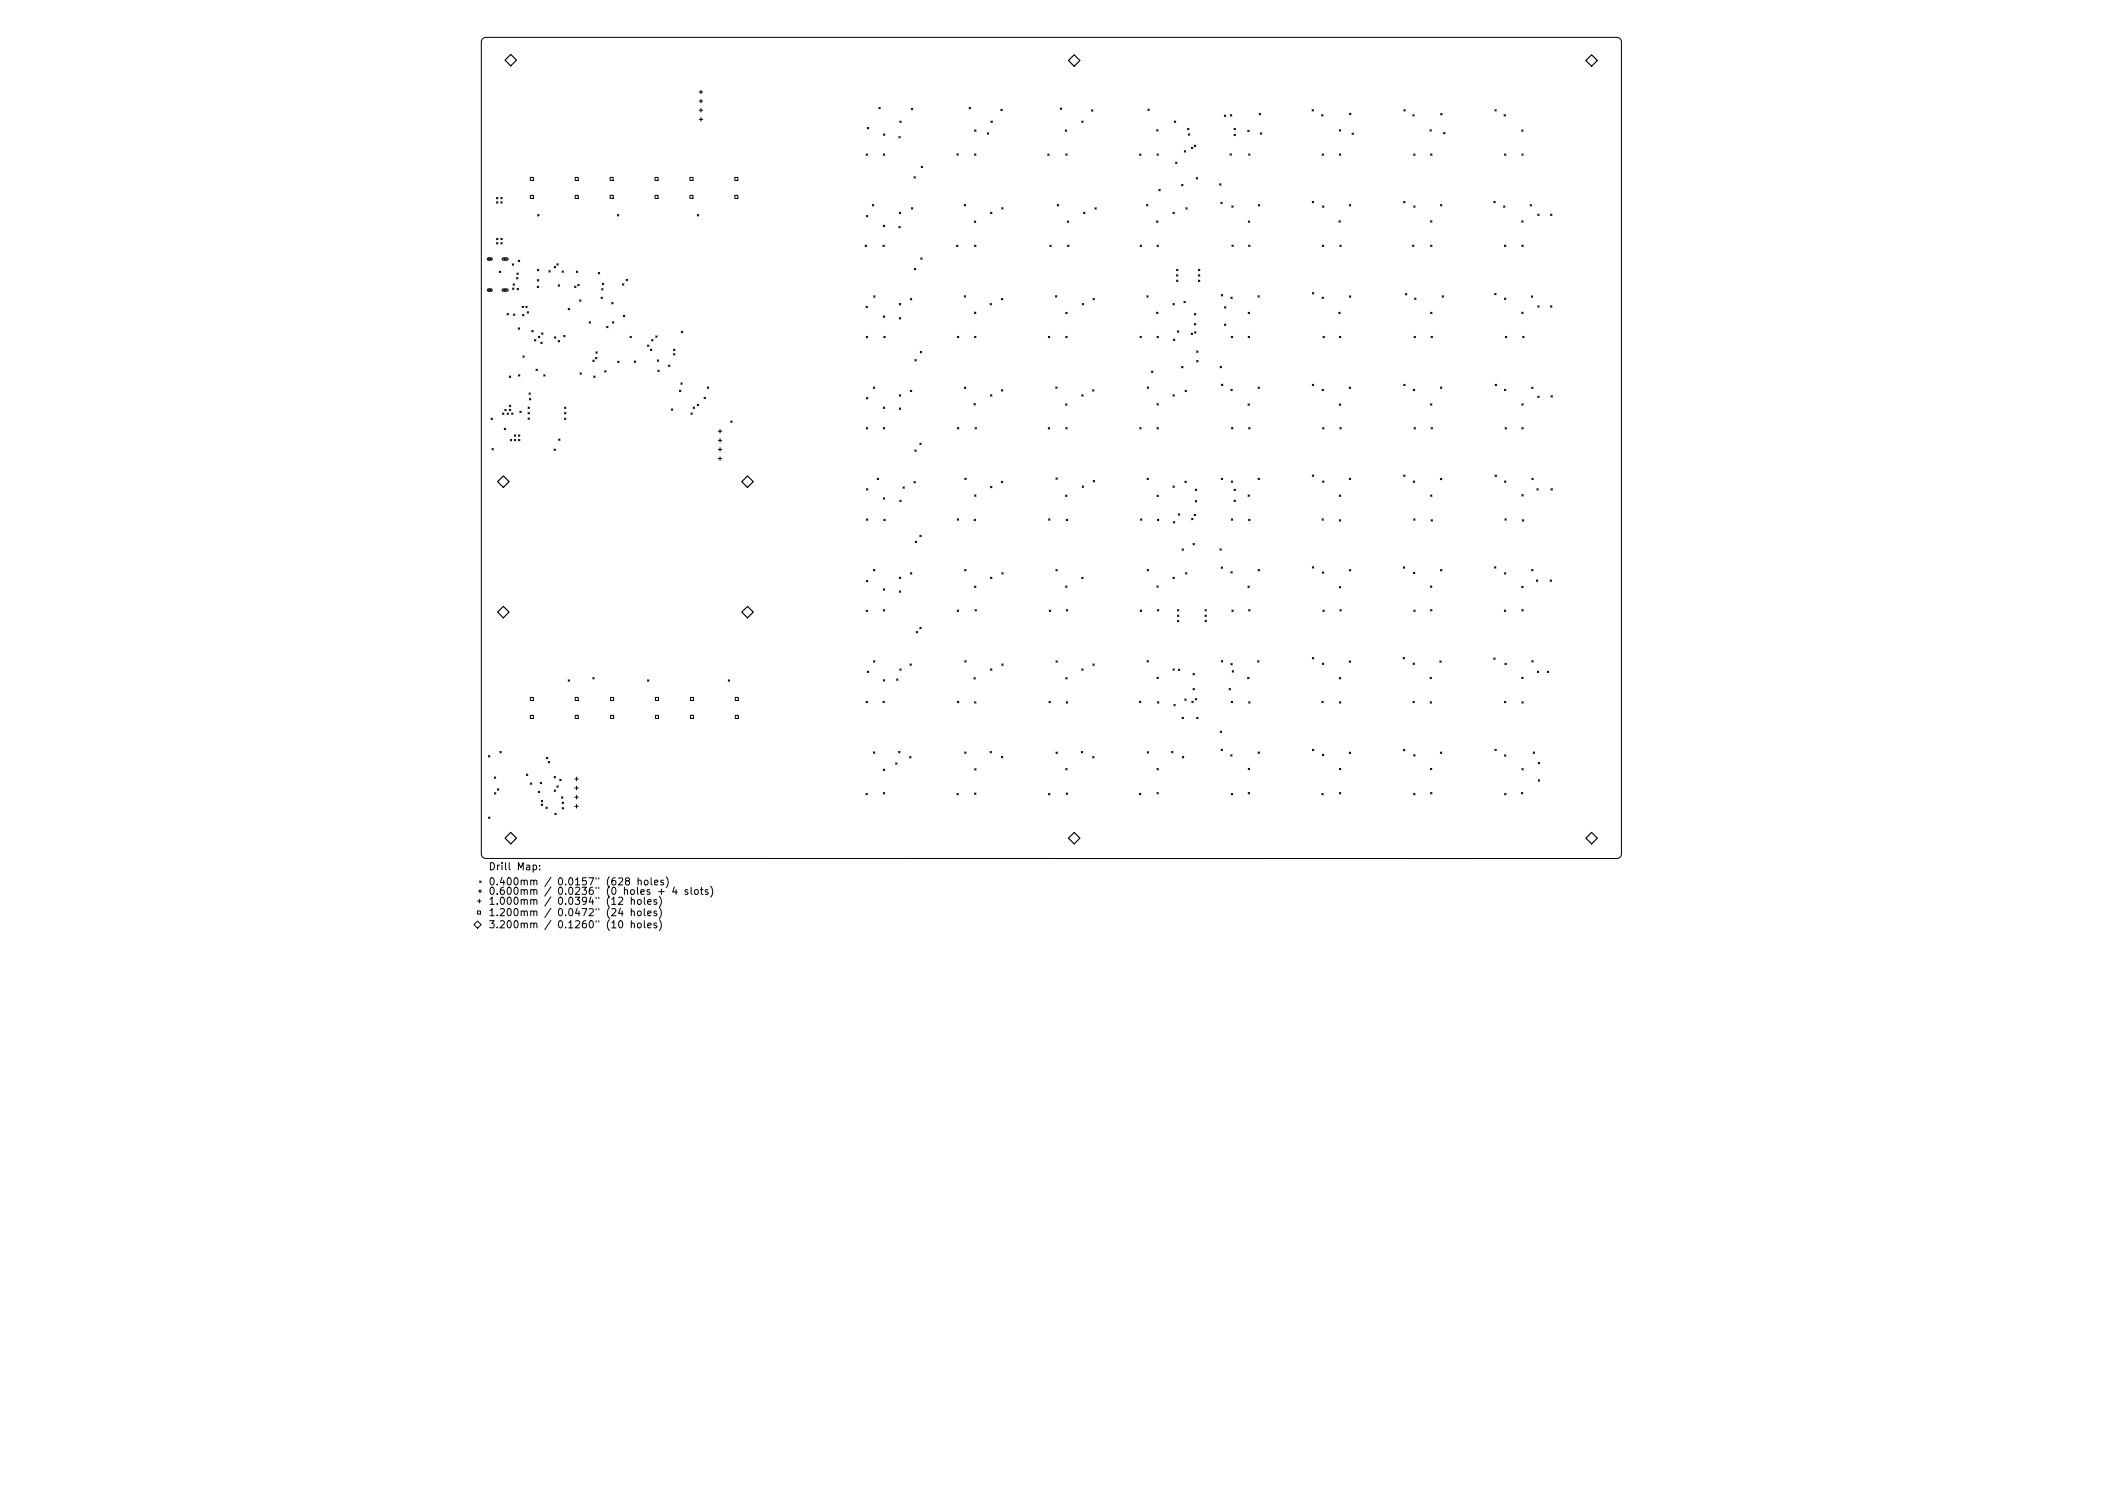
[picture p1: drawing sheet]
<svg xmlns="http://www.w3.org/2000/svg" width="297mm" height="210mm" viewBox="0 0 297 210" stroke-linecap="round" stroke-linejoin="round" font-family="sans-serif">
<defs><g id="words">
<g font-size="1.4">
<text x="69" y="122.9">Drill Map:</text>
<text x="69" y="125">0.400mm / 0.0157&quot; (628 holes)</text>
<text x="69" y="126.3">0.600mm / 0.0236&quot; (0 holes + 4 slots)</text>
<text x="69" y="127.8">1.000mm / 0.0394&quot; (12 holes)</text>
<text x="69" y="129.4">1.200mm / 0.0472&quot; (24 holes)</text>
<text x="69" y="131.1">3.200mm / 0.1260&quot; (10 holes)</text>
</g>
</g></defs>
<g fill="none" stroke="#000" stroke-width=".14">
<path d="M68.2 5.5l.4-.2h159.8a.64 .64 0 0 1 .6 .6v114.7a.65 .65 0 0 1-.6 .6h-159.8a.64 .64 0 0 1-.6-.6v-114.7zM98.8 13h.5M98.8 14.3h.5M98.8 15.6h.5M98.8 16.9h.5M99 12.7v.5M99 14v.5M99 15.3v.5M99 16.6v.5M122.5 18l.2 .2M122.7 18l-.2 .2M124.1 15.2l.2 .2"/>
<path d="M124.3 15.2l-.2 .2M124.8 18.9l.2 .2M125 18.9l-.2 .2M127 19.3l.2 .2M127.1 17.1l.2 .2M127.2 19.3l-.2 .2M127.3 17.1l-.2 .2M128.7 15.3l.2 .2M128.9 15.3l-.2 .2M136.9 15.2l.2 .2M137.1 15.2l-.2 .2M137.7 18.3l.2 .2"/>
<path d="M137.9 18.3l-.2 .2M139.5 18.8l.2 .2M139.7 18.8l-.2 .2M140 17.1l.2 .2M140.2 17.1l-.2 .2M141.4 15.4l.2 .2M141.6 15.4l-.2 .2M149.8 15.2l.2 .2M150 15.2l-.2 .2M150.5 18.3l.2 .2M150.7 18.3l-.2 .2M152.8 17.1l.2 .2"/>
<path d="M153 17.1l-.2 .2M154.2 15.5l.2 .2M154.4 15.5l-.2 .2M162.1 15.4l.2 .2M162.3 15.4l-.2 .2M163.4 18.3l.2 .2M163.6 18.3l-.2 .2M165.9 17.1l.2 .2M166.1 17.1l-.2 .2M167.7 18.1l.2 .2M167.9 18.9l.2 .2M167.9 18.1l-.2 .2"/>
<path d="M168.1 18.9l-.2 .2M172.9 16.3l.2 .2M173.1 16.3l-.2 .2M173.8 16.2l.2 .2M174 16.2l-.2 .2M174.3 18.1l.2 .2M174.3 19l.2 .2M174.5 18.1l-.2 .2M174.5 19l-.2 .2M176.2 18.4l.2 .2M176.4 18.4l-.2 .2M177.8 16l.3 .2"/>
<path d="M178 18.8l.2 .2M178.1 16l-.3 .2M178.2 18.8l-.2 .2M185.3 15.5l.2 .2M185.5 15.5l-.2 .2M186.7 16.2l.2 .2M186.9 16.2l-.2 .2M189.2 18.3l.2 .2M189.4 18.3l-.2 .2M190.6 16l.2 .2M190.8 16l-.2 .2M191 18.8l.2 .2"/>
<path d="M191.2 18.8l-.2 .2M198.3 15.5l.2 .2M198.5 15.5l-.2 .2M199.6 16.2l.2 .2M199.8 16.2l-.2 .2M202 18.3l.2 .2M202.2 18.3l-.2 .2M203.5 16l.2 .2M203.7 16l-.2 .2M203.9 18.7l.2 .2M204.1 18.7l-.2 .2M211.1 15.5l.2 .2"/>
<path d="M211.3 15.5l-.2 .2M212.4 16.2l.2 .2M212.6 16.2l-.2 .2M214.9 18.3l.2 .2M215.1 18.3l-.2 .2M68.9 36.5l.5-.1 .1 .2-.1 .1h-.5l-.1-.1zM70.1 27.9l.2 .2M70.1 28.5l.2 .2M70.1 33.6l.2 .2M70.1 34.3l.2 .2M70.3 27.9l-.2 .2M70.3 28.5l-.2 .2"/>
<path d="M70.3 33.6l-.2 .2M70.3 34.3l-.2 .2M70.5 38.3l.2 .2M70.7 38.3l-.2 .2M70.7 28.5l.2 .2M70.7 27.9l.2 .2M70.7 34.3l.2 .2M70.7 33.6l.2 .2M70.9 27.9l-.2 .2M70.9 28.5l-.2 .2M70.9 33.6l-.2 .2M70.9 34.3l-.2 .2"/>
<path d="M71 36.5l.6-.1 .2 .2-.2 .1h-.6l-.1-.1zM72.4 37.3l.2 .2M72.6 37.3l-.2 .2M73 39.2l.2 .2M73 38.6l.2 .2M73.2 39.2l-.2 .2M73.2 36.7l.2 .3M73.2 38.6l-.2 .2M73.4 36.7l-.2 .3M74.9 25h.4v.5h-.4zM74.9 27.6h.4v.4h-.4zM75.9 38l.2 .2"/>
<path d="M75.9 39.5l.2 .2M75.9 30.3l.2 .2M76.1 38l-.2 .2M76.1 39.5l-.2 .2M76.1 30.3l-.2 .2M77.5 38.2l.2 .2M77.7 38.2l-.2 .2M78.3 37.6l.2 .2M78.5 37.6l-.2 .2M78.7 37.2l.2 .2M78.9 37.2l-.2 .2M79.4 38.3l.2 .2"/>
<path d="M79.6 38.3l-.2 .2M81.2 25h.5v.5h-.5zM81.2 27.6h.5v.4h-.5zM81.4 38.3l.2 .2M81.6 38.3l-.2 .2M84.5 38.5l.2 .2M84.7 38.5l-.2 .2M85.1 40l.2 .2M85.3 40l-.2 .2M86.2 25h.4v.5h-.4zM86.2 27.6h.4v.4h-.4zM87.2 30.3l.2 .2"/>
<path d="M87.4 30.3l-.2 .2M88.4 39.4l.2 .2M88.6 39.4l-.2 .2M92.5 25h.4v.5h-.4zM92.5 27.6h.4v.4h-.4zM97.4 25h.5v.5h-.5zM97.4 27.6h.5v.4h-.5zM98.5 30.3l.2 .2M98.7 30.3l-.2 .2M103.8 25h.4v.5h-.4zM103.8 27.6h.4v.4h-.4zM122.2 34.6l.2 .2"/>
<path d="M122.3 21.7l.2 .2M122.4 30.4l.2 .2M122.4 34.6l-.2 .2M122.5 21.7l-.2 .2M122.6 30.4l-.2 .2M123.2 28.9l.2 .2M123.4 28.9l-.2 .2M124.7 34.6l.2 .2M124.8 31.8l.2 .2M124.8 21.7l.2 .2M124.9 34.6l-.2 .2M125 31.8l-.2 .2"/>
<path d="M125 21.7l-.2 .2M127 32l.2 .2M127 30l.2 .2M127.2 32l-.2 .2M127.2 30l-.2 .2M128.7 29.3l.2 .2M128.9 29.3l-.2 .2M129.1 24.9l.2 .3M129.1 37.9l.2 .2M129.3 24.9l-.2 .3M129.3 37.9l-.2 .2M130 36.4l.3 .2"/>
<path d="M130.1 23.5l.2 .2M130.3 36.4l-.3 .2M130.3 23.5l-.2 .2M135.1 34.6l.2 .2M135.2 21.7l.2 .2M135.3 34.6l-.2 .2M135.4 21.7l-.2 .2M136.2 28.9l.2 .2M136.4 28.9l-.2 .2M137.6 31.2l.2 .2M137.6 21.7l.3 .2M137.6 34.6l.3 .2"/>
<path d="M137.8 31.2l-.2 .2M137.9 21.7l-.3 .2M137.9 34.6l-.3 .2M139.9 30l.2 .2M140.1 30l-.2 .2M141.5 29.3l.2 .2M141.7 29.3l-.2 .2M148 21.7l.2 .2M148.2 21.7l-.2 .2M148.3 34.6l.2 .2M148.5 34.6l-.2 .2M149.3 28.9l.2 .2"/>
<path d="M149.5 28.9l-.2 .2M150.5 21.7l.2 .2M150.7 21.7l-.2 .2M150.8 31.2l.2 .2M150.8 34.6l.2 .2M151 31.2l-.2 .2M151 34.6l-.2 .2M153 30l.2 .2M153.2 30l-.2 .2M154.6 29.3l.2 .2M154.8 29.3l-.2 .2M160.9 21.7l.3 .2"/>
<path d="M161 34.6l.2 .2M161.2 21.7l-.3 .2M161.2 34.6l-.2 .2M161.9 28.9l.2 .2M162.1 28.9l-.2 .2M163.4 31.2l.2 .2M163.4 21.7l.2 .2M163.4 34.6l.2 .2M163.6 31.2l-.2 .2M163.6 21.7l-.2 .2M163.6 34.6l-.2 .2M163.7 26.8l.2 .2"/>
<path d="M163.9 26.8l-.2 .2M165.7 30l.2 .2M165.9 30l-.2 .2M166 22.9l.3 .2M166.2 38l.2 .2M166.2 38.8l.2 .2M166.2 39.5l.2 .2M166.3 22.9l-.3 .2M166.4 38l-.2 .2M166.4 38.8l-.2 .2M166.4 39.5l-.2 .2M166.9 26l.2 .2"/>
<path d="M167.1 26l-.2 .2M167.3 21.3l.2 .2M167.5 21.3l-.2 .2M167.5 29.3l.2 .2M167.7 29.3l-.2 .2M168.3 20.8l.2 .2M168.5 20.8l-.2 .2M168.7 20.5l.2 .2M168.9 20.5l-.2 .2M169 25.1l.2 .2M169.2 25.1l-.2 .2M169.3 38l.2 .2"/>
<path d="M169.3 38.8l.2 .2M169.3 39.6l.2 .2M169.5 38l-.2 .2M169.5 38.8l-.2 .2M169.5 39.6l-.2 .2M172.3 25.9l.2 .2M172.4 28.6l.2 .2M172.5 25.9l-.2 .2M172.6 28.6l-.2 .2M173.7 21.7l.2 .2M173.9 21.7l-.2 .2M174 29.1l.2 .2"/>
<path d="M174 34.6l.2 .2M174.2 29.1l-.2 .2M174.2 34.6l-.2 .2M176.3 31.2l.2 .2M176.4 21.7l.2 .2M176.4 34.6l.2 .2M176.5 31.2l-.2 .2M176.6 21.7l-.2 .2M176.6 34.6l-.2 .2M177.7 28.9l.2 .2M177.9 28.9l-.2 .2M185.3 28.4l.2 .2"/>
<path d="M185.5 28.4l-.2 .2M186.7 21.7l.2 .2M186.8 34.6l.2 .2M186.8 29.1l.2 .2M186.9 21.7l-.2 .2M187 34.6l-.2 .2M187 29.1l-.2 .2M189.1 31.2l.2 .2M189.2 21.7l.2 .2M189.2 34.6l.2 .2M189.3 31.2l-.2 .2M189.4 21.7l-.2 .2"/>
<path d="M189.4 34.6l-.2 .2M190.6 28.9l.2 .2M190.8 28.9l-.2 .2M198.3 28.4l.2 .2M198.5 28.4l-.2 .2M199.5 34.6l.2 .2M199.7 21.7l.2 .2M199.7 29.1l.2 .2M199.7 34.6l-.2 .2M199.9 21.7l-.2 .2M199.9 29.1l-.2 .2M202.1 31.2l.2 .2"/>
<path d="M202.1 34.6l.2 .2M202.1 21.7l.2 .2M202.3 31.2l-.2 .2M202.3 34.6l-.2 .2M202.3 21.7l-.2 .2M203.5 28.9l.2 .2M203.7 28.9l-.2 .2M211 28.4l.2 .2M211.2 28.4l-.2 .2M212.4 29.1l.2 .2M212.5 34.6l.2 .2M212.5 21.7l.2 .2"/>
<path d="M212.6 29.1l-.2 .2M212.7 34.6l-.2 .2M212.7 21.7l-.2 .2M214.9 31.2l.2 .2M214.9 21.7l.2 .2M214.9 34.6l.2 .2M215.1 31.2l-.2 .2M215.1 21.7l-.2 .2M215.1 34.6l-.2 .2M216.1 28.9l.2 .2M216.3 28.9l-.2 .2M217.2 30.2l.2 .2"/>
<path d="M217.4 30.2l-.2 .2M219 30.2l.2 .2M219.2 30.2l-.2 .2M68.9 40.9l.5-.1 .1 .2-.1 .1h-.5l-.1-.1zM69.4 59l.2 .2M69.6 59l-.2 .2M71 40.9l.6-.1 .2 .2-.2 .1h-.6l-.1-.1zM71 58.3l.2 .2M71.2 58.3l-.2 .2M71.3 57.8l.2 .2M71.5 57.8l-.2 .2M71.6 44.3l.2 .2"/>
<path d="M71.6 58.3l.2 .2M71.8 44.3l-.2 .2M71.8 58.3l-.2 .2M71.9 53.1l.2 .2M71.9 57.2l.2 .2M71.9 57.8l.2 .2M72.1 53.1l-.2 .2M72.1 57.2l-.2 .2M72.1 57.8l-.2 .2M72.3 58.3l.2 .2M72.4 40.7l.2 .2M72.5 58.3l-.2 .2"/>
<path d="M72.5 40.1l.2 .2M72.5 44.3l.2 .2M72.6 40.7l-.2 .2M72.7 40.1l-.2 .2M72.7 44.3l-.2 .2M73 40.7l.2 .2M73.2 46.3l.2 .2M73.2 52.9l.2 .2M73.2 40.7l-.2 .2M73.4 46.3l-.2 .2M73.4 58.1l.2 .2M73.4 52.9l-.2 .2"/>
<path d="M73.6 58.1l-.2 .2M73.7 43.2l.2 .2M73.8 44.4l.2 .2M73.9 50.2l.2 .3M73.9 43.2l-.2 .2M74 44.4l-.2 .2M74.1 50.2l-.2 .3M74.3 43.2l.2 .2M74.5 44l.2 .2M74.5 43.2l-.2 .2M74.6 57.5l.2 .2M74.6 58.2l.2 .3"/>
<path d="M74.6 59l.2 .2M74.7 44l-.2 .2M74.7 55.5l.2 .2M74.8 56.3l.2 .2M74.8 58.2l-.2 .3M74.8 57.5l-.2 .2M74.8 59l-.2 .2M74.9 55.5l-.2 .2M75 56.3l-.2 .2M75.1 46.7l.2 .2M75.3 46.7l-.2 .2M75.5 48l.2 .2"/>
<path d="M75.7 48l-.2 .2M75.7 52.1l.2 .2M75.9 40.4l.2 .2M75.9 52.1l-.2 .2M76 47.5l.2 .2M76.1 40.4l-.2 .2M76.2 47.5l-.2 .2M76.4 48.3l.2 .2M76.5 47l.2 .2M76.6 48.3l-.2 .2M76.7 47l-.2 .2M76.8 52.9l.2 .2"/>
<path d="M77 52.9l-.2 .2M78.3 47.6l.2 .2M78.5 47.6l-.2 .2M78.8 48.1l.2 .2M78.8 40.2l.2 .2M79 40.2l-.2 .2M79 48.1l-.2 .2M79.6 47.4l.2 .2M79.7 57.5l.2 .2M79.7 58.2l.2 .3M79.7 59l.2 .2M79.8 47.4l-.2 .2"/>
<path d="M79.9 57.5l-.2 .2M79.9 58.2l-.2 .3M79.9 59l-.2 .2M80.3 43.5l.2 .2M80.5 43.5l-.2 .2M81.2 40.4l.2 .2M81.4 40.4l-.2 .2M81.6 40.1l.2 .3M81.8 40.1l-.2 .3M81.9 42.3l.2 .2M81.9 52.6l.2 .2M82.1 42.3l-.2 .2"/>
<path d="M82.1 52.6l-.2 .2M83.2 45.4l.2 .2M83.4 45.4l-.2 .2M83.7 50.8l.2 .2M83.9 53.1l.2 .2M83.9 50.8l-.2 .2M84.1 53.1l-.2 .2M84.1 50.5l.2 .2M84.2 49.7l.2 .2M84.3 50.5l-.2 .2M84.4 49.7l-.2 .2M84.9 42l.2 .2"/>
<path d="M85 40.8l.2 .2M85.1 42l-.2 .2M85.2 40.8l-.2 .2M85.4 52.3l.2 .2M85.6 52.3l-.2 .2M85.7 46.1l.2 .2M85.9 46.1l-.2 .2M86.4 42.7l.2 .2M86.5 45.4l.2 .2M86.6 42.7l-.2 .2M86.7 45.4l-.2 .2M87.2 51l.2 .2"/>
<path d="M87.4 51l-.2 .2M87.9 40.1l.2 .2M88 44.5l.2 .2M88.1 40.1l-.2 .2M88.2 44.5l-.2 .2M89 47.5l.2 .2M89.2 47.5l-.2 .2M89.6 51l.2 .2M89.8 51l-.2 .2M91.5 48.7l.2 .2M91.7 48.7l-.2 .2M91.9 49.3l.2 .2"/>
<path d="M92 47.9l.2 .2M92.1 49.3l-.2 .2M92.2 47.9l-.2 .2M92.6 47.4l.2 .2M92.8 47.4l-.2 .2M92.8 50.8l.2 .2M92.9 52.3l.2 .2M93 50.8l-.2 .2M93.1 52.3l-.2 .2M94.4 51.6l.2 .2M94.6 51.6l-.2 .2M94.8 57.7l.2 .2"/>
<path d="M95 57.7l-.2 .2M95.1 49.9l.2 .2M95.1 49.3l.2 .2M95.3 49.3l-.2 .2M95.3 49.9l-.2 .2M96 55.1l.2 .2M96.2 54.1l.2 .2M96.2 55.1l-.2 .2M96.2 46.8l.2 .2M96.4 54.1l-.2 .2M96.4 46.8l-.2 .2M97.6 58.3l.2 .2"/>
<path d="M97.8 58.3l-.2 .2M97.9 57.5l.2 .2M98.1 57.5l-.2 .2M98.5 57.1l.2 .2M98.7 57.1l-.2 .2M99.4 56.1l.2 .2M99.6 56.1l-.2 .2M99.9 54.6l.2 .2M100.1 54.6l-.2 .2M103.2 59.4l.2 .2M103.4 59.4l-.2 .2M122.3 43.2l.2 .2"/>
<path d="M122.3 47.5l.2 .2M122.4 56.1l.2 .2M122.5 43.2l-.2 .2M122.5 47.5l-.2 .2M122.6 56.1l-.2 .2M123.3 54.6l.3 .3M123.4 41.8l.2 .2M123.6 54.6l-.3 .3M123.6 41.8l-.2 .2M124.8 57.5l.2 .2M124.8 44.6l.2 .2M124.8 47.5l.2 .2"/>
<path d="M125 57.5l-.2 .2M125 44.6l-.2 .2M125 47.5l-.2 .2M127 42.9l.2 .2M127 44.9l.2 .2M127 55.7l.2 .2M127 57.6l.2 .2M127.2 55.7l-.2 .2M127.2 42.9l-.2 .2M127.2 44.9l-.2 .2M127.2 57.6l-.2 .2M128.6 42.2l.2 .2"/>
<path d="M128.6 55.1l.2 .2M128.8 42.2l-.2 .2M128.8 55.1l-.2 .2M129.2 50.8l.2 .2M129.4 50.8l-.2 .2M130 49.6l.2 .2M130.2 49.6l-.2 .2M135.2 47.5l.2 .2M135.4 47.5l-.2 .2M136.2 41.8l.2 .2M136.2 54.7l.2 .2M136.4 41.8l-.2 .2"/>
<path d="M136.4 54.7l-.2 .2M137.6 57l.2 .2M137.6 44.1l.2 .2M137.6 47.5l.3 .2M137.8 57l-.2 .2M137.8 44.1l-.2 .2M137.9 47.5l-.3 .2M139.8 42.9l.2 .2M139.9 55.7l.2 .2M140 42.9l-.2 .2M140.1 55.7l-.2 .2M141.4 42.1l.2 .2"/>
<path d="M141.4 55l.2 .2M141.6 42.1l-.2 .2M141.6 55l-.2 .2M148.1 47.5l.2 .2M148.3 47.5l-.2 .2M149.1 41.8l.2 .2M149.1 54.6l.2 .2M149.3 41.8l-.2 .2M149.3 54.6l-.2 .2M150.5 57l.2 .2M150.5 47.5l.2 .2M150.5 44.1l.2 .2"/>
<path d="M150.7 57l-.2 .2M150.7 47.5l-.2 .2M150.7 44.1l-.2 .2M152.8 55.7l.2 .2M152.9 42.9l.2 .2M153 55.7l-.2 .2M153.1 42.9l-.2 .2M154.3 55l.2 .2M154.4 42.1l.2 .2M154.5 55l-.2 .2M154.6 42.1l-.2 .2M161 47.5l.2 .2"/>
<path d="M161.2 47.5l-.2 .2M162 41.8l.2 .2M162 54.6l.2 .2M162.2 41.8l-.2 .2M162.2 54.6l-.2 .2M162.6 52.4l.2 .2M162.8 52.4l-.2 .2M163.4 44.1l.2 .2M163.4 57l.2 .2M163.4 47.5l.2 .2M163.6 44.1l-.2 .2M163.6 57l-.2 .2"/>
<path d="M163.6 47.5l-.2 .2M165.7 42.9l.2 .2M165.7 55.7l.2 .2M165.7 47.9l.2 .2M165.9 42.9l-.2 .2M165.9 55.7l-.2 .2M165.9 47.9l-.2 .2M166.3 46.7l.2 .2M166.5 46.7l-.2 .2M166.9 51.7l.2 .2M167.1 51.7l-.2 .2M167.2 42.5l.2 .3"/>
<path d="M167.4 55.1l.2 .2M167.4 42.5l-.2 .3M167.6 55.1l-.2 .2M168.2 47l.2 .2M168.4 47l-.2 .2M168.7 45.7l.2 .2M168.7 44.3l.2 .2M168.7 46.8l.2 .2M168.9 44.3l-.2 .2M168.9 45.7l-.2 .2M168.9 46.8l-.2 .2M169 49.6l.2 .2"/>
<path d="M169 50.9l.2 .2M169.2 49.6l-.2 .2M169.2 50.9l-.2 .2M172.3 51.7l.2 .2M172.5 41.6l.2 .2M172.5 54.2l.2 .3M172.5 51.7l-.2 .2M172.7 41.6l-.2 .2M172.7 54.2l-.2 .3M172.9 43.3l.3 .2M172.9 45.8l.3 .2M173.2 43.3l-.3 .2"/>
<path d="M173.2 45.8l-.3 .2M173.8 42l.3 .2M173.8 55l.3 .2M173.9 47.5l.2 .2M174.1 42l-.3 .2M174.1 55l-.3 .2M174.1 47.5l-.2 .2M176.3 57l.2 .2M176.3 44.1l.2 .2M176.3 47.5l.2 .2M176.5 57l-.2 .2M176.5 44.1l-.2 .2"/>
<path d="M176.5 47.5l-.2 .2M177.7 41.8l.2 .2M177.7 54.6l.2 .3M177.9 41.8l-.2 .2M177.9 54.6l-.2 .3M185.4 54.3l.2 .2M185.4 41.3l.2 .2M185.6 54.3l-.2 .2M185.6 41.3l-.2 .2M186.7 42l.2 .2M186.7 55l.2 .2M186.9 47.5l.2 .2"/>
<path d="M186.9 42l-.2 .2M186.9 55l-.2 .2M187.1 47.5l-.2 .2M189.1 44.1l.2 .2M189.2 57l.2 .2M189.2 47.5l.2 .2M189.3 44.1l-.2 .2M189.4 57l-.2 .2M189.4 47.5l-.2 .2M190.6 54.7l.2 .2M190.6 41.8l.2 .2M190.8 54.7l-.2 .2"/>
<path d="M190.8 41.8l-.2 .2M198.3 54.3l.2 .2M198.5 54.3l-.2 .2M198.5 41.4l.2 .2M198.7 41.4l-.2 .2M199.6 55l.2 .2M199.7 47.5l.2 .2M199.8 42.1l.2 .2M199.8 55l-.2 .2M199.9 47.5l-.2 .2M200 42.1l-.2 .2M202.1 57l.2 .2"/>
<path d="M202.1 44.1l.2 .2M202.1 47.5l.2 .2M202.3 57l-.2 .2M202.3 44.1l-.2 .2M202.3 47.5l-.2 .2M203.5 54.6l.2 .2M203.7 54.6l-.2 .2M203.7 41.8l.2 .2M203.9 41.8l-.2 .2M211.1 41.4l.2 .2M211.2 54.3l.2 .2M211.3 41.4l-.2 .2"/>
<path d="M211.4 54.3l-.2 .2M212.5 42.1l.2 .2M212.5 55l.2 .2M212.6 47.5l.2 .2M212.7 42.1l-.2 .2M212.7 55l-.2 .2M212.8 47.5l-.2 .2M214.9 44.1l.2 .2M214.9 57l.2 .2M215.1 47.5l.2 .2M215.1 44.1l-.2 .2M215.1 57l-.2 .2"/>
<path d="M215.3 47.5l-.2 .2M216.3 41.8l.2 .2M216.3 54.7l.2 .2M216.5 41.8l-.2 .2M216.5 54.7l-.2 .2M217.2 43.2l.2 .2M217.2 55.9l.2 .2M217.4 43.2l-.2 .2M217.4 55.9l-.2 .2M219 43.2l.2 .2M219.1 55.9l.2 .2M219.2 43.2l-.2 .2"/>
<path d="M219.3 55.9l-.2 .2M69.5 63.3l.2 .2M69.7 63.3l-.2 .2M71.2 60.5l.2 .2M71.4 60.5l-.2 .2M72.1 62l.2 .3M72.3 62l-.2 .3M72.6 61.4l.3 .2M72.6 62l.3 .3M72.9 61.4l-.3 .2M72.9 62l-.3 .3M73.2 61.4l.2 .2"/>
<path d="M73.2 62l.2 .3M73.4 61.4l-.2 .2M73.4 62l-.2 .3M78.3 63.4l.2 .2M78.5 63.4l-.2 .2M78.9 62l.2 .2M79.1 62l-.2 .2M101.4 60.9h.6M101.4 62.2h.6M101.4 63.5h.6M101.4 64.8h.6M101.7 60.6v.5"/>
<path d="M101.7 61.9v.5M101.7 63.2v.5M101.7 64.5v.5M122.4 60.4l.2 .2M122.4 73.3l.2 .2M122.4 69l.2 .2M122.6 60.4l-.2 .2M122.6 73.3l-.2 .2M122.6 69l-.2 .2M123.9 67.5l.2 .2M124.1 67.5l-.2 .2M124.8 70.3l.2 .2"/>
<path d="M124.8 60.4l.2 .2M124.8 73.3l.2 .2M125 70.3l-.2 .2M125 60.4l-.2 .2M125 73.3l-.2 .2M127.1 70.6l.2 .2M127.3 70.6l-.2 .2M127.5 68.7l.2 .3M127.7 68.7l-.2 .3M129.1 68l.2 .2M129.2 63.5l.2 .2M129.3 76.4l.2 .2"/>
<path d="M129.3 68l-.2 .2M129.4 63.5l-.2 .2M129.5 76.4l-.2 .2M129.9 62.6l.2 .2M129.9 75.6l.2 .2M130.1 62.6l-.2 .2M130.1 75.6l-.2 .2M135.2 73.3l.2 .2M135.2 60.4l.2 .2M135.4 73.3l-.2 .2M135.4 60.4l-.2 .2M136.3 67.5l.2 .2"/>
<path d="M136.5 67.5l-.2 .2M137.6 73.3l.2 .2M137.7 69.9l.2 .2M137.7 60.4l.2 .2M137.8 73.3l-.2 .2M137.9 69.9l-.2 .2M137.9 60.4l-.2 .2M139.9 68.7l.2 .2M140.1 68.7l-.2 .2M141.4 68l.2 .2M141.6 68l-.2 .2M148.1 60.4l.2 .2"/>
<path d="M148.1 73.3l.2 .2M148.3 60.4l-.2 .2M148.3 73.3l-.2 .2M149.1 67.5l.2 .2M149.3 67.5l-.2 .2M150.5 69.9l.2 .2M150.5 60.4l.2 .2M150.6 73.3l.2 .2M150.7 69.9l-.2 .2M150.7 60.4l-.2 .2M150.8 73.3l-.2 .2M152.9 68.6l.2 .2"/>
<path d="M153.1 68.6l-.2 .2M154.4 67.9l.2 .2M154.6 67.9l-.2 .2M161 60.4l.2 .2M161.1 73.3l.2 .2M161.2 60.4l-.2 .2M161.3 73.3l-.2 .2M162 67.5l.2 .2M162.2 67.5l-.2 .2M163.4 60.4l.2 .2M163.4 69.9l.2 .2M163.5 73.3l.2 .2"/>
<path d="M163.6 60.4l-.2 .2M163.6 69.9l-.2 .2M163.7 73.3l-.2 .2M165.7 68.6l.2 .2M165.7 73.7l.2 .2M165.9 68.6l-.2 .2M165.9 73.7l-.2 .2M166.4 72.5l.2 .3M166.6 72.5l-.2 .3M167 77.5l.2 .2M167.2 77.5l-.2 .2M167.4 67.9l.2 .2"/>
<path d="M167.6 67.9l-.2 .2M168.3 73.2l.2 .2M168.5 76.7l.2 .2M168.5 73.2l-.2 .2M168.7 72.6l.2 .2M168.7 76.7l-.2 .2M168.8 69.1l.2 .2M168.8 70.7l.2 .2M168.9 72.6l-.2 .2M169 69.1l-.2 .2M169 70.7l-.2 .2M172.3 77.5l.2 .2"/>
<path d="M172.5 77.5l-.2 .2M172.5 67.5l.2 .2M172.7 67.5l-.2 .2M173.9 67.9l.2 .2M173.9 73.3l.2 .2M173.9 60.4l.2 .2M174.1 67.9l-.2 .2M174.1 73.3l-.2 .2M174.1 60.4l-.2 .2M174.3 69.1l.2 .2M174.3 70.6l.2 .2M174.5 69.1l-.2 .2"/>
<path d="M174.5 70.6l-.2 .2M176.3 69.9l.2 .2M176.4 60.4l.2 .2M176.4 73.3l.2 .2M176.5 69.9l-.2 .2M176.6 60.4l-.2 .2M176.6 73.3l-.2 .2M177.7 67.5l.2 .2M177.9 67.5l-.2 .2M185.4 67.1l.2 .2M185.6 67.1l-.2 .2M186.7 73.3l.2 .2"/>
<path d="M186.8 67.9l.2 .2M186.8 60.4l.2 .2M186.9 73.3l-.2 .2M187 67.9l-.2 .2M187 60.4l-.2 .2M189.2 69.9l.2 .2M189.2 73.4l.2 .2M189.2 60.4l.2 .2M189.4 69.9l-.2 .2M189.4 73.4l-.2 .2M189.4 60.4l-.2 .2M190.6 67.5l.2 .2"/>
<path d="M190.8 67.5l-.2 .2M198.3 67.1l.2 .2M198.5 67.1l-.2 .2M199.6 67.9l.2 .2M199.7 73.3l.2 .2M199.7 60.4l.2 .2M199.8 67.9l-.2 .2M199.9 73.3l-.2 .2M199.9 60.4l-.2 .2M202.1 69.9l.2 .2M202.1 60.4l.2 .2M202.1 73.4l.2 .2"/>
<path d="M202.3 69.9l-.2 .2M202.3 60.4l-.2 .2M202.3 73.4l-.2 .2M203.4 67.5l.2 .2M203.6 67.5l-.2 .2M211.2 67.1l.2 .2M211.4 67.1l-.2 .2M212.5 67.9l.2 .2M212.6 73.3l.2 .2M212.6 60.4l.2 .2M212.7 67.9l-.2 .2M212.8 73.3l-.2 .2"/>
<path d="M212.8 60.4l-.2 .2M214.9 69.8l.2 .2M214.9 60.4l.2 .2M215 73.4l.2 .2M215.1 69.8l-.2 .2M215.1 60.4l-.2 .2M215.2 73.4l-.2 .2M216.4 67.5l.2 .2M216.6 67.5l-.2 .2M217.1 69l.2 .2M217.3 69l-.2 .2M219.1 69l.2 .2"/>
<path d="M219.3 69l-.2 .2M74.9 98.5h.4v.4h-.4zM80.3 96l.2 .2M80.5 96l-.2 .2M81.2 98.5h.5v.4h-.5zM83.7 95.7l.2 .2M83.9 95.7l-.2 .2M86.2 98.5h.5v.4h-.5zM91.5 96l.2 .2M91.7 96l-.2 .2M92.6 98.5h.4v.4h-.4zM97.5 98.5h.4v.4h-.4z"/>
<path d="M102.9 96l.2 .2M103.1 96l-.2 .2M103.9 98.5h.4v.4h-.4zM122.3 86.2l.2 .2M122.3 99l.2 .2M122.4 82l.2 .2M122.5 94.8l.2 .2M122.5 86.2l-.2 .2M122.5 99l-.2 .2M122.6 82l-.2 .2M122.7 94.8l-.2 .2M123.4 80.4l.2 .2"/>
<path d="M123.4 93.3l.2 .2M123.6 80.4l-.2 .2M123.6 93.3l-.2 .2M124.7 99l.2 .2M124.8 83.1l.2 .3M124.8 86.1l.2 .2M124.8 96l.2 .2M124.9 99l-.2 .2M125 83.1l-.2 .3M125 86.1l-.2 .2M125 96l-.2 .2M126.6 95.9l.2 .2"/>
<path d="M126.8 95.9l-.2 .2M127 81.5l.2 .2M127 83.4l.2 .2M127.1 94.4l.2 .3M127.2 81.5l-.2 .2M127.2 83.4l-.2 .2M127.3 94.4l-.2 .3M128.5 93.7l.2 .3M128.6 80.9l.2 .2M128.7 93.7l-.2 .3M128.8 80.9l-.2 .2M129.4 89.2l.2 .2"/>
<path d="M129.6 89.2l-.2 .2M129.9 88.6l.2 .2M130.1 88.6l-.2 .2M135.2 86.1l.2 .2M135.2 99l.2 .2M135.4 86.1l-.2 .2M135.4 99l-.2 .2M136.3 80.4l.2 .2M136.3 93.3l.2 .2M136.5 80.4l-.2 .2M136.5 93.3l-.2 .2M137.6 95.7l.2 .2"/>
<path d="M137.6 82.8l.2 .2M137.6 99.1l.3 .2M137.7 86.1l.2 .2M137.8 95.7l-.2 .2M137.8 82.8l-.2 .2M137.9 99.1l-.3 .2M137.9 86.1l-.2 .2M139.9 81.5l.2 .2M139.9 94.4l.2 .3M140.1 94.4l-.2 .3M140.1 81.5l-.2 .2M141.5 93.7l.2 .3"/>
<path d="M141.5 80.9l.2 .2M141.7 93.7l-.2 .3M141.7 80.9l-.2 .2M148.2 99l.2 .2M148.2 86.1l.2 .2M148.4 99l-.2 .2M148.4 86.1l-.2 .2M149.1 80.4l.2 .2M149.1 93.3l.3 .2M149.3 80.4l-.2 .2M149.4 93.3l-.3 .2M150.5 82.7l.2 .2"/>
<path d="M150.5 95.7l.2 .2M150.6 86.1l.2 .2M150.6 99.1l.2 .2M150.7 82.7l-.2 .2M150.7 95.7l-.2 .2M150.8 86.1l-.2 .2M150.8 99.1l-.2 .2M152.8 81.5l.2 .2M152.8 94.4l.2 .3M153 81.5l-.2 .2M153 94.4l-.2 .3M154.4 93.8l.2 .2"/>
<path d="M154.6 93.8l-.2 .2M160.9 99l.2 .2M161 86.1l.3 .2M161.1 99l-.2 .2M161.3 86.1l-.3 .2M162 93.3l.2 .2M162 80.4l.2 .2M162.2 93.3l-.2 .2M162.2 80.4l-.2 .2M163.4 82.7l.2 .2M163.4 95.6l.2 .2M163.5 86.1l.2 .2"/>
<path d="M163.5 99.1l.2 .2M163.6 82.7l-.2 .2M163.6 95.6l-.2 .2M163.7 99.1l-.2 .2M163.7 86.1l-.2 .2M165.7 81.5l.2 .2M165.7 94.4l.2 .3M165.8 99.5l.2 .2M165.9 81.5l-.2 .2M165.9 94.4l-.2 .3M166 99.5l-.2 .2M166.3 86.1l.2 .2"/>
<path d="M166.3 86.8l.2 .3M166.3 87.6l.2 .2M166.4 94.5l.2 .2M166.5 86.1l-.2 .2M166.5 86.8l-.2 .3M166.5 87.6l-.2 .2M166.6 94.5l-.2 .2M167.3 98.7l.2 .2M167.4 80.9l.2 .2M167.5 98.7l-.2 .2M167.6 80.9l-.2 .2M168.3 99l.2 .2"/>
<path d="M168.5 97.2l.2 .2M168.5 95.1l.2 .2M168.5 99l-.2 .2M168.7 95.1l-.2 .2M168.7 97.2l-.2 .2M168.8 98.6l.2 .2M169 98.6l-.2 .2M170.2 86.1l.2 .2M170.2 86.8l.2 .3M170.2 87.6l.2 .2M170.4 86.1l-.2 .2M170.4 86.8l-.2 .3"/>
<path d="M170.4 87.6l-.2 .2M172.5 80.1l.2 .2M172.5 93.3l.2 .2M172.7 80.1l-.2 .2M172.7 93.3l-.2 .2M173.6 97.2l.2 .2M173.8 97.2l-.2 .2M173.8 80.7l.3 .2M173.8 93.7l.3 .2M173.9 99l.2 .2M174 86.1l.2 .2M174 94.7l.2 .2"/>
<path d="M174.1 80.7l-.3 .2M174.1 93.7l-.3 .2M174.1 99l-.2 .2M174.2 86.1l-.2 .2M174.2 94.7l-.2 .2M176.2 95.6l.2 .2M176.3 82.8l.2 .2M176.4 86.1l.2 .2M176.4 99.1l.2 .2M176.4 95.6l-.2 .2M176.5 82.8l-.2 .2M176.6 86.1l-.2 .2"/>
<path d="M176.6 99.1l-.2 .2M177.6 93.3l.2 .2M177.7 80.4l.2 .2M177.8 93.3l-.2 .2M177.9 80.4l-.2 .2M185.4 80l.2 .2M185.4 92.8l.2 .2M185.6 80l-.2 .2M185.6 92.8l-.2 .2M186.7 99l.2 .2M186.8 80.8l.2 .2M186.8 93.6l.2 .2"/>
<path d="M186.9 86.1l.2 .2M186.9 99l-.2 .2M187 80.8l-.2 .2M187 93.6l-.2 .2M187.1 86.1l-.2 .2M189.2 95.7l.2 .2M189.2 82.8l.2 .2M189.2 99.1l.2 .2M189.2 86.1l.2 .2M189.4 95.7l-.2 .2M189.4 82.8l-.2 .2M189.4 99.1l-.2 .2"/>
<path d="M189.4 86.1l-.2 .2M190.6 93.3l.2 .2M190.6 80.4l.2 .2M190.8 93.3l-.2 .2M190.8 80.4l-.2 .2M198.2 92.8l.2 .2M198.2 80l.2 .2M198.4 92.8l-.2 .2M198.4 80l-.2 .2M199.6 99l.2 .2M199.6 93.6l.2 .2M199.6 80.8l.2 .2"/>
<path d="M199.7 86.1l.2 .2M199.8 99l-.2 .2M199.8 93.6l-.2 .2M199.8 80.8l-.2 .2M199.9 86.1l-.2 .2M202 95.6l.2 .2M202 99.1l.2 .2M202 82.7l.2 .2M202.1 86.1l.2 .2M202.2 95.6l-.2 .2M202.2 99.1l-.2 .2M202.2 82.7l-.2 .2"/>
<path d="M202.3 86.1l-.2 .2M203.4 93.3l.2 .2M203.5 80.4l.2 .2M203.6 93.3l-.2 .2M203.7 80.4l-.2 .2M211 92.9l.2 .2M211.1 80l.2 .2M211.2 92.9l-.2 .2M211.3 80l-.2 .2M212.5 86.1l.2 .2M212.5 80.9l.2 .2M212.5 99l.2 .2"/>
<path d="M212.6 93.7l.2 .2M212.7 86.1l-.2 .2M212.7 80.9l-.2 .2M212.7 99l-.2 .2M212.8 93.7l-.2 .2M214.9 82.8l.2 .2M214.9 95.6l.2 .2M214.9 99.1l.2 .2M214.9 86.1l.2 .2M215.1 82.8l-.2 .2M215.1 95.6l-.2 .2M215.1 86.1l-.2 .2"/>
<path d="M215.1 99.1l-.2 .2M216.3 80.4l.2 .2M216.4 93.3l.2 .2M216.5 80.4l-.2 .2M216.6 93.3l-.2 .2M217 81.9l.2 .2M217.1 94.8l.2 .2M217.2 81.9l-.2 .2M217.3 94.8l-.2 .2M218.6 94.8l.2 .2M218.8 94.8l-.2 .2M218.9 81.9l.2 .2"/>
<path d="M219.1 81.9l-.2 .2M69 106.7l.2 .2M69 115.4l.2 .2M69.2 106.7l-.2 .2M69.2 115.4l-.2 .2M69.8 109.7l.2 .2M69.8 111.9l.2 .2M70 109.7l-.2 .2M70 111.9l-.2 .2M70.3 111.4l.2 .2M70.5 111.4l-.2 .2M70.6 106.1l.2 .2"/>
<path d="M70.8 106.1l-.2 .2M74.3 109.3l.3 .2M74.6 109.3l-.3 .2M74.9 101h.4v.4h-.4zM74.9 110.5l.2 .2M75.1 110.5l-.2 .2M76 111.7l.2 .2M76.2 111.7l-.2 .2M76.3 110.5l.2 .2M76.5 113l.2 .2M76.5 113.5l.2 .2M76.5 110.5l-.2 .2"/>
<path d="M76.7 113l-.2 .2M76.7 113.5l-.2 .2M77.1 114l.2 .2M77.2 106.9l.2 .2M77.3 114l-.2 .2M77.4 106.9l-.2 .2M77.4 107.5l.2 .2M77.6 107.5l-.2 .2M78.3 109.6l.2 .2M78.3 111.6l.2 .2M78.4 114.8l.2 .2M78.5 109.6l-.2 .2"/>
<path d="M78.5 111.6l-.2 .2M78.6 114.8l-.2 .2M78.6 111l.3 .2M78.9 111l-.3 .2M79.1 110l.2 .2M79.3 110l-.2 .2M79.3 112.5l.2 .2M79.4 113.3l.2 .2M79.4 114l.2 .2M79.5 112.5l-.2 .2M79.6 113.3l-.2 .2M79.6 114l-.2 .2"/>
<path d="M81.2 110h.5M81.2 111.3h.5M81.2 112.6h.5M81.2 113.9h.5M81.2 101h.5v.4h-.5zM81.4 109.7v.5M81.4 111v.5M81.4 112.3v.5M81.4 113.6v.5M86.2 101h.5v.4h-.5zM92.6 101h.4v.4h-.4zM97.5 101h.4v.4h-.4z"/>
<path d="M103.9 101h.4v.4h-.4zM122.3 112l.2 .2M122.5 112l-.2 .2M123.4 106.2l.2 .2M123.6 106.2l-.2 .2M124.8 108.6l.2 .2M124.8 111.9l.2 .2M125 108.6l-.2 .2M125 111.9l-.2 .2M126.5 107.7l.2 .2M126.7 107.7l-.2 .2M126.9 106.1l.2 .2"/>
<path d="M127.1 106.1l-.2 .2M128.5 106.8l.2 .2M128.7 106.8l-.2 .2M135.2 112l.2 .2M135.4 112l-.2 .2M136.3 106.2l.2 .2M136.5 106.2l-.2 .2M137.6 112l.3 .2M137.7 108.5l.2 .2M137.9 112l-.3 .2M137.9 108.5l-.2 .2M139.8 106.1l.2 .2"/>
<path d="M140 106.1l-.2 .2M141.4 106.8l.2 .2M141.6 106.8l-.2 .2M148.1 112l.2 .2M148.3 112l-.2 .2M149.1 106.2l.3 .2M149.4 106.2l-.3 .2M150.5 108.5l.2 .2M150.6 112l.2 .2M150.7 108.5l-.2 .2M150.8 112l-.2 .2M152.7 106.1l.2 .2"/>
<path d="M152.9 106.1l-.2 .2M154.3 106.8l.2 .2M154.5 106.8l-.2 .2M160.9 112l.2 .2M161.1 112l-.2 .2M162 106.1l.2 .2M162.2 106.1l-.2 .2M163.4 108.5l.2 .2M163.4 111.9l.2 .2M163.6 108.5l-.2 .2M163.6 111.9l-.2 .2M165.5 106.1l.2 .2"/>
<path d="M165.7 106.1l-.2 .2M167 101.3l.2 .2M167 106.8l.2 .2M167.2 101.3l-.2 .2M167.2 106.8l-.2 .2M169 101.3l.2 .2M169.2 101.3l-.2 .2M172.3 103.2l.2 .2M172.5 105.8l.2 .2M172.5 103.2l-.2 .2M172.7 105.8l-.2 .2M173.8 106.6l.2 .2"/>
<path d="M173.9 112l.2 .2M174 106.6l-.2 .2M174.1 112l-.2 .2M176.3 111.9l.2 .2M176.3 108.5l.2 .2M176.5 111.9l-.2 .2M176.5 108.5l-.2 .2M177.7 106.2l.2 .2M177.9 106.2l-.2 .2M185.4 105.8l.2 .2M185.6 105.8l-.2 .2M186.7 112l.2 .2"/>
<path d="M186.8 106.5l.2 .2M186.9 112l-.2 .2M187 106.5l-.2 .2M189.2 108.5l.2 .2M189.2 111.9l.2 .2M189.4 108.5l-.2 .2M189.4 111.9l-.2 .2M190.6 106.2l.2 .2M190.8 106.2l-.2 .2M198.2 105.8l.2 .2M198.4 105.8l-.2 .2M199.7 112l.2 .2"/>
<path d="M199.7 106.6l.2 .2M199.9 112l-.2 .2M199.9 106.6l-.2 .2M202 108.5l.2 .2M202.1 111.9l.2 .2M202.2 108.5l-.2 .2M202.3 111.9l-.2 .2M203.4 106.2l.2 .2M203.6 106.2l-.2 .2M211.1 105.8l.2 .2M211.3 105.8l-.2 .2M212.5 106.6l.2 .2"/>
<path d="M212.5 112l.2 .2M212.7 106.6l-.2 .2M212.7 112l-.2 .2M214.9 111.9l.2 .2M215 108.5l.2 .2M215.1 111.9l-.2 .2M215.2 108.5l-.2 .2M216.6 106.2l.2 .2M216.8 106.2l-.2 .2M217.3 107.7l.2 .2M217.3 110.1l.2 .2M217.5 107.7l-.2 .2"/>
<path d="M217.5 110.1l-.2 .2M66.9 130.6l.6-.5 .5 .5-.5 .5zM67.4 128.6h.5v.5h-.5zM67.5 127.2h.5M67.7 127v.5M67.8 124.4l.2 .2M68 124.4l-.2 .2M75.3 122.2h.3l.2 .1-.1 .5h-.4M76.2 122.7v.1M76.2 122.2v.1M87.4 126.8l.4-.1 .2 .3-.7 .7h.7M87.5 130.1l.1-.1a.54 .54 0 0 1 .4 .5 .54 .54 0 0 1-.4 .5l-.1-.1-.1-.3z"/>
<path d="M87.6 128.2l-.2 .8h.6M88.5 124.4l-.2-.2 .1-.2 .1-.1 .3 .1 .1 .1v.2l-.5 .1-.1 .2 .1 .3 .1 .1 .3-.1 .1-.1v-.2l-.2-.2M89.2 127.1l.1-.1 .3 .1v.6M89.2 128.7l.1-.1 .3 .1v.6M89.2 130.4l.1-.1 .3 .1v.6M89.2 126.7v1M89.2 128.3v1M89.2 130v1M90.1 128.7l.1-.1 .3 .1 .1 .4-.1 .2h-.3l-.1-.1zM90.1 124.4l.2-.1h.2l.1 .7M90.1 127.1l.3-.1 .2 .2v.3l-.2 .2h-.3l-.1-.2zM90.1 130.4l.3-.1 .2 .2v.3l-.2 .2h-.3l-.1-.2z"/>
<path d="M90.1 123.9v1.1M91 126.7v.9l.1 .1M91 128.3v.9l.1 .1M91 130v.9l.1 .1M91.1 124.4l.1-.1 .3 .1v.4l-.1 .1-.2 .1-.1-.1zM91.5 127.4l.5-.1-.1-.2-.3-.1-.1 .2v.5h.4M91.5 129l.5-.1-.1-.2-.3-.1-.1 .2v.5h.4M91.5 130.7l.5-.1-.1-.2-.3-.1-.1 .2v.5h.4M92 123.9v.9l.1 .2M92.5 124.6l.4-.1v-.2h-.3l-.1 .1v.5h.4M92.7 127.1l-.2-.1-.1 .2v.1l.3 .1v.3h-.3M92.7 128.7l-.2-.1-.1 .2v.1l.3 .1v.3h-.3"/>
<path d="M92.7 130.4l-.2-.1-.1 .2v.1l.3 .1v.3h-.3M93 125.9h.8M93.1 126.5a1.16 1.16 0 0 1 0 1.6M93.1 128.2a1.16 1.16 0 0 1 0 1.5M93.1 129.9a1.16 1.16 0 0 1 0 1.5M93.4 125.5v.8M93.7 124.3h-.2l-.2 .1 .1 .2 .3 .1v.2h-.4M94.1 123.8a1.16 1.16 0 0 1 0 1.5M95.3 125.2l-.3 .8h.6M95.5 125.6v.7M97.1 125.7l-.2-.1-.1 .2v.1l.3 .1v.2h-.3M97.6 125.3v.9l.2 .1"/>
<path d="M98.2 125.7l.1-.1 .3 .1v.4l-.1 .1-.2 .1-.1-.1zM98.9 125.6h.4M99.1 125.3v.9l.2 .1M100 125.7l-.3-.1-.1 .2v.1l.4 .1v.2h-.4M100.4 125.1a1.16 1.16 0 0 1 0 1.6"/>
<circle cx="69.2" cy="36.6" r=".15"/>
<circle cx="71.3" cy="36.6" r=".15"/>
<circle cx="69.2" cy="41" r=".15"/>
<circle cx="71.3" cy="41" r=".15"/>
<circle cx="67.8" cy="125.8" r=".15"/>
</g>
<path d="M71.3 8.5l.8-.8 .9 .8-.9 .8zM150.9 8.5l.8-.8 .8 .8-.8 .9zM224 8.5l.8-.8 .8 .8-.8 .9zM70.3 68l.8-.8 .8 .8-.8 .8zM104.8 68l.8-.8 .8 .8-.8 .8zM70.3 86.4l.8-.8 .8 .8-.8 .8zM104.8 86.4l.8-.8 .8 .8-.8 .8zM71.3 118.4l.8-.9 .9 .9-.9 .8zM150.9 118.4l.8-.9 .8 .9-.8 .8zM224 118.4l.8-.9 .8 .9-.8 .8z" fill="none" stroke="#000" stroke-width=".16"/>
<use href="#words"/>
</svg>
